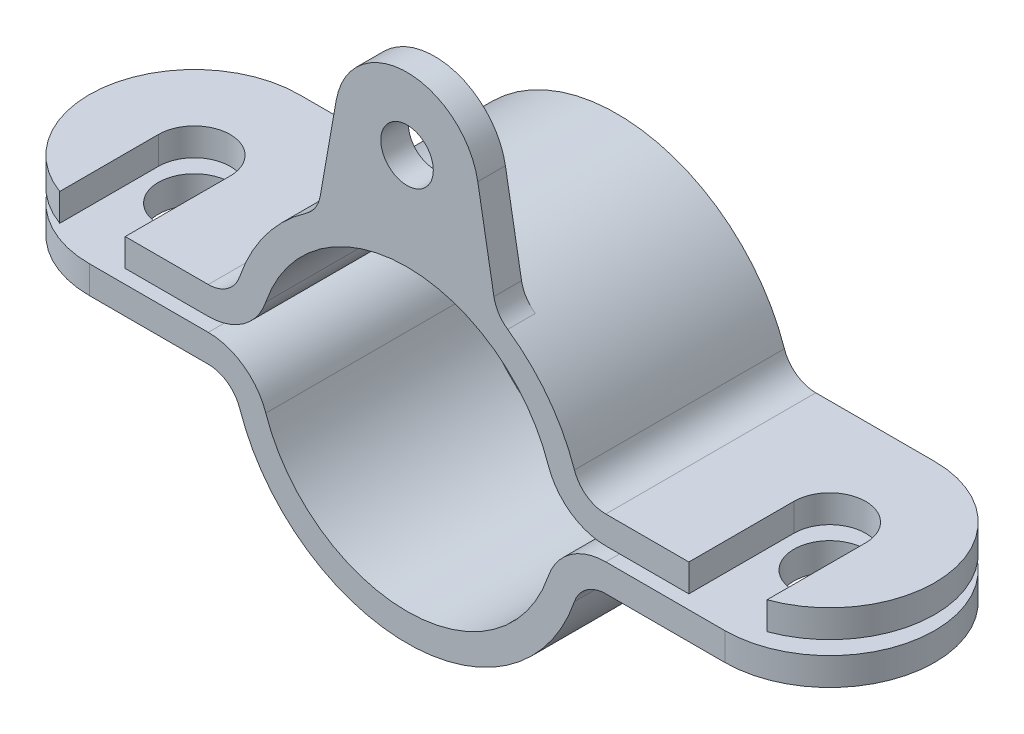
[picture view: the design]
ISO-10303-21;
HEADER;
FILE_DESCRIPTION(('STEP AP214'),'2;1');
FILE_NAME('part.step','',(''),(''),'','','');
FILE_SCHEMA(('AUTOMOTIVE_DESIGN { 1 0 10303 214 1 1 1 1 }'));
ENDSEC;
DATA;
#1=APPLICATION_CONTEXT('core data for automotive mechanical design processes');
#2=APPLICATION_PROTOCOL_DEFINITION('international standard','automotive_design',2000,#1);
#3=PRODUCT_CONTEXT('',#1,'mechanical');
#4=PRODUCT('Part','Part','',(#3));
#5=PRODUCT_RELATED_PRODUCT_CATEGORY('part','',(#4));
#6=PRODUCT_DEFINITION_FORMATION('','',#4);
#7=PRODUCT_DEFINITION_CONTEXT('part definition',#1,'design');
#8=PRODUCT_DEFINITION('design','',#6,#7);
#9=PRODUCT_DEFINITION_SHAPE('','',#8);
#10=(LENGTH_UNIT() NAMED_UNIT(*) SI_UNIT(.MILLI.,.METRE.));
#11=(NAMED_UNIT(*) PLANE_ANGLE_UNIT() SI_UNIT($,.RADIAN.));
#12=(NAMED_UNIT(*) SI_UNIT($,.STERADIAN.) SOLID_ANGLE_UNIT());
#13=UNCERTAINTY_MEASURE_WITH_UNIT(LENGTH_MEASURE(1.E-05),#10,'distance_accuracy_value','');
#14=(GEOMETRIC_REPRESENTATION_CONTEXT(3) GLOBAL_UNCERTAINTY_ASSIGNED_CONTEXT((#13)) GLOBAL_UNIT_ASSIGNED_CONTEXT((#10,
#11,#12)) REPRESENTATION_CONTEXT('',''));
#15=CARTESIAN_POINT('',(0.,0.,0.));
#16=DIRECTION('',(0.,0.,1.));
#17=DIRECTION('',(1.,0.,0.));
#18=AXIS2_PLACEMENT_3D('',#15,#16,#17);
#19=CARTESIAN_POINT('',(57.5,-6.25,-19.));
#20=DIRECTION('',(0.,1.,0.));
#21=DIRECTION('',(-1.,0.,0.));
#22=AXIS2_PLACEMENT_3D('',#19,#20,#21);
#23=CYLINDRICAL_SURFACE('',#22,19.);
#24=DIRECTION('',(0.,1.,0.));
#25=VECTOR('',#24,1.);
#26=CARTESIAN_POINT('',(64.,-6.25,-1.14642892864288));
#27=LINE('',#26,#25);
#28=CARTESIAN_POINT('',(64.,1.25,-1.14642892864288));
#29=VERTEX_POINT('',#28);
#30=CARTESIAN_POINT('',(64.,6.25,-1.14642892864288));
#31=VERTEX_POINT('',#30);
#32=EDGE_CURVE('E236',#29,#31,#27,.T.);
#33=ORIENTED_EDGE('',*,*,#32,.F.);
#34=CARTESIAN_POINT('',(57.5,1.25,-19.));
#35=DIRECTION('',(0.,1.,0.));
#36=DIRECTION('',(0.,0.,1.));
#37=AXIS2_PLACEMENT_3D('',#34,#35,#36);
#38=CIRCLE('',#37,19.);
#39=CARTESIAN_POINT('',(57.5,1.25,-38.));
#40=VERTEX_POINT('',#39);
#41=EDGE_CURVE('E256',#40,#29,#38,.F.);
#42=ORIENTED_EDGE('',*,*,#41,.F.);
#43=DIRECTION('',(0.,-1.,0.));
#44=VECTOR('',#43,1.);
#45=CARTESIAN_POINT('',(57.5,-6.25,-38.));
#46=LINE('',#45,#44);
#47=CARTESIAN_POINT('',(57.5,6.25,-38.));
#48=VERTEX_POINT('',#47);
#49=EDGE_CURVE('E259',#48,#40,#46,.T.);
#50=ORIENTED_EDGE('',*,*,#49,.F.);
#51=CARTESIAN_POINT('',(57.5,6.25,-19.));
#52=DIRECTION('',(0.,1.,0.));
#53=DIRECTION('',(0.,0.,1.));
#54=AXIS2_PLACEMENT_3D('',#51,#52,#53);
#55=CIRCLE('',#54,19.);
#56=EDGE_CURVE('E287',#31,#48,#55,.T.);
#57=ORIENTED_EDGE('',*,*,#56,.F.);
#58=EDGE_LOOP('',(#33,#42,#50,#57));
#59=FACE_BOUND('',#58,.T.);
#60=ADVANCED_FACE('F46',(#59),#23,.T.);
#61=CARTESIAN_POINT('',(0.,0.,-38.));
#62=DIRECTION('',(0.,0.,1.));
#63=DIRECTION('',(1.,0.,0.));
#64=AXIS2_PLACEMENT_3D('',#61,#62,#63);
#65=PLANE('',#64);
#66=CARTESIAN_POINT('',(-35.9713427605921,12.25,-38.));
#67=DIRECTION('',(0.,0.,-1.));
#68=DIRECTION('',(1.,0.,0.));
#69=AXIS2_PLACEMENT_3D('',#66,#67,#68);
#70=CIRCLE('',#69,11.);
#71=CARTESIAN_POINT('',(-25.5585856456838,8.70394736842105,-38.));
#72=VERTEX_POINT('',#71);
#73=CARTESIAN_POINT('',(-35.9713427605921,1.25,-38.));
#74=VERTEX_POINT('',#73);
#75=EDGE_CURVE('E252',#72,#74,#70,.T.);
#76=ORIENTED_EDGE('',*,*,#75,.T.);
#77=DIRECTION('',(-1.,0.,0.));
#78=VECTOR('',#77,1.);
#79=CARTESIAN_POINT('',(-35.9713427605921,1.25,-38.));
#80=LINE('',#79,#78);
#81=CARTESIAN_POINT('',(-57.5,1.25,-38.));
#82=VERTEX_POINT('',#81);
#83=EDGE_CURVE('E372',#74,#82,#80,.T.);
#84=ORIENTED_EDGE('',*,*,#83,.T.);
#85=DIRECTION('',(0.,1.,0.));
#86=VECTOR('',#85,1.);
#87=CARTESIAN_POINT('',(-57.5,6.25,-38.));
#88=LINE('',#87,#86);
#89=CARTESIAN_POINT('',(-57.5,6.25,-38.));
#90=VERTEX_POINT('',#89);
#91=EDGE_CURVE('E266',#82,#90,#88,.T.);
#92=ORIENTED_EDGE('',*,*,#91,.T.);
#93=DIRECTION('',(-1.,0.,0.));
#94=VECTOR('',#93,1.);
#95=CARTESIAN_POINT('',(-31.3837139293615,6.25,-38.));
#96=LINE('',#95,#94);
#97=CARTESIAN_POINT('',(-35.9713427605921,6.25,-38.));
#98=VERTEX_POINT('',#97);
#99=EDGE_CURVE('E291',#98,#90,#96,.T.);
#100=ORIENTED_EDGE('',*,*,#99,.F.);
#101=CARTESIAN_POINT('',(-35.9713427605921,12.25,-38.));
#102=DIRECTION('',(0.,0.,1.));
#103=DIRECTION('',(1.,0.,0.));
#104=AXIS2_PLACEMENT_3D('',#101,#102,#103);
#105=CIRCLE('',#104,6.);
#106=CARTESIAN_POINT('',(-30.2916570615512,10.3157894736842,-38.));
#107=VERTEX_POINT('',#106);
#108=EDGE_CURVE('E260',#98,#107,#105,.T.);
#109=ORIENTED_EDGE('',*,*,#108,.T.);
#110=CARTESIAN_POINT('',(0.,0.,-38.));
#111=DIRECTION('',(0.,0.,1.));
#112=DIRECTION('',(1.,0.,0.));
#113=AXIS2_PLACEMENT_3D('',#110,#111,#112);
#114=CIRCLE('',#113,32.);
#115=CARTESIAN_POINT('',(30.2916570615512,10.3157894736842,-38.));
#116=VERTEX_POINT('',#115);
#117=EDGE_CURVE('E307',#116,#107,#114,.T.);
#118=ORIENTED_EDGE('',*,*,#117,.F.);
#119=CARTESIAN_POINT('',(35.9713427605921,12.25,-38.));
#120=DIRECTION('',(0.,0.,1.));
#121=DIRECTION('',(1.,0.,0.));
#122=AXIS2_PLACEMENT_3D('',#119,#120,#121);
#123=CIRCLE('',#122,6.);
#124=CARTESIAN_POINT('',(35.9713427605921,6.25,-38.));
#125=VERTEX_POINT('',#124);
#126=EDGE_CURVE('E257',#116,#125,#123,.T.);
#127=ORIENTED_EDGE('',*,*,#126,.T.);
#128=DIRECTION('',(-1.,0.,0.));
#129=VECTOR('',#128,1.);
#130=CARTESIAN_POINT('',(31.3837139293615,6.25,-38.));
#131=LINE('',#130,#129);
#132=EDGE_CURVE('E288',#48,#125,#131,.T.);
#133=ORIENTED_EDGE('',*,*,#132,.F.);
#134=ORIENTED_EDGE('',*,*,#49,.T.);
#135=DIRECTION('',(-1.,0.,0.));
#136=VECTOR('',#135,1.);
#137=CARTESIAN_POINT('',(76.5,1.25,-38.));
#138=LINE('',#137,#136);
#139=CARTESIAN_POINT('',(35.9713427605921,1.25,-38.));
#140=VERTEX_POINT('',#139);
#141=EDGE_CURVE('E382',#40,#140,#138,.T.);
#142=ORIENTED_EDGE('',*,*,#141,.T.);
#143=CARTESIAN_POINT('',(35.9713427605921,12.25,-38.));
#144=DIRECTION('',(0.,0.,-1.));
#145=DIRECTION('',(1.,0.,0.));
#146=AXIS2_PLACEMENT_3D('',#143,#144,#145);
#147=CIRCLE('',#146,11.);
#148=CARTESIAN_POINT('',(25.5585856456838,8.70394736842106,-38.));
#149=VERTEX_POINT('',#148);
#150=EDGE_CURVE('E379',#140,#149,#147,.T.);
#151=ORIENTED_EDGE('',*,*,#150,.T.);
#152=CARTESIAN_POINT('',(0.,0.,-38.));
#153=DIRECTION('',(0.,0.,1.));
#154=DIRECTION('',(1.,0.,0.));
#155=AXIS2_PLACEMENT_3D('',#152,#153,#154);
#156=CIRCLE('',#155,27.);
#157=EDGE_CURVE('E317',#149,#72,#156,.T.);
#158=ORIENTED_EDGE('',*,*,#157,.T.);
#159=EDGE_LOOP('',(#76,#84,#92,#100,#109,#118,#127,#133,#134,#142,#151,#158));
#160=FACE_BOUND('',#159,.T.);
#161=ADVANCED_FACE('F420',(#160),#65,.F.);
#162=CARTESIAN_POINT('',(0.,0.,0.));
#163=DIRECTION('',(0.,0.,1.));
#164=DIRECTION('',(1.,0.,0.));
#165=AXIS2_PLACEMENT_3D('',#162,#163,#164);
#166=PLANE('',#165);
#167=DIRECTION('',(0.,1.,0.));
#168=VECTOR('',#167,1.);
#169=CARTESIAN_POINT('',(-51.,-32.,0.));
#170=LINE('',#169,#168);
#171=CARTESIAN_POINT('',(-51.,1.25,0.));
#172=VERTEX_POINT('',#171);
#173=CARTESIAN_POINT('',(-51.,6.25,0.));
#174=VERTEX_POINT('',#173);
#175=EDGE_CURVE('E214',#172,#174,#170,.T.);
#176=ORIENTED_EDGE('',*,*,#175,.F.);
#177=DIRECTION('',(-1.,0.,0.));
#178=VECTOR('',#177,1.);
#179=CARTESIAN_POINT('',(-35.9713427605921,1.25,0.));
#180=LINE('',#179,#178);
#181=CARTESIAN_POINT('',(-35.9713427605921,1.25,0.));
#182=VERTEX_POINT('',#181);
#183=EDGE_CURVE('E363',#182,#172,#180,.T.);
#184=ORIENTED_EDGE('',*,*,#183,.F.);
#185=CARTESIAN_POINT('',(-35.9713427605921,12.25,0.));
#186=DIRECTION('',(0.,0.,-1.));
#187=DIRECTION('',(1.,0.,0.));
#188=AXIS2_PLACEMENT_3D('',#185,#186,#187);
#189=CIRCLE('',#188,11.);
#190=CARTESIAN_POINT('',(-25.5585856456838,8.70394736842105,0.));
#191=VERTEX_POINT('',#190);
#192=EDGE_CURVE('E361',#191,#182,#189,.T.);
#193=ORIENTED_EDGE('',*,*,#192,.F.);
#194=CARTESIAN_POINT('',(0.,0.,0.));
#195=DIRECTION('',(0.,0.,1.));
#196=DIRECTION('',(1.,0.,0.));
#197=AXIS2_PLACEMENT_3D('',#194,#195,#196);
#198=CIRCLE('',#197,27.);
#199=CARTESIAN_POINT('',(25.5585856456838,8.70394736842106,0.));
#200=VERTEX_POINT('',#199);
#201=EDGE_CURVE('E358',#200,#191,#198,.T.);
#202=ORIENTED_EDGE('',*,*,#201,.F.);
#203=CARTESIAN_POINT('',(35.9713427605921,12.25,0.));
#204=DIRECTION('',(0.,0.,-1.));
#205=DIRECTION('',(1.,0.,0.));
#206=AXIS2_PLACEMENT_3D('',#203,#204,#205);
#207=CIRCLE('',#206,11.);
#208=CARTESIAN_POINT('',(35.9713427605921,1.25,0.));
#209=VERTEX_POINT('',#208);
#210=EDGE_CURVE('E355',#209,#200,#207,.T.);
#211=ORIENTED_EDGE('',*,*,#210,.F.);
#212=DIRECTION('',(-1.,0.,0.));
#213=VECTOR('',#212,1.);
#214=CARTESIAN_POINT('',(0.,1.25,0.));
#215=LINE('',#214,#213);
#216=CARTESIAN_POINT('',(51.,1.25,0.));
#217=VERTEX_POINT('',#216);
#218=EDGE_CURVE('E253',#217,#209,#215,.T.);
#219=ORIENTED_EDGE('',*,*,#218,.F.);
#220=DIRECTION('',(0.,1.,0.));
#221=VECTOR('',#220,1.);
#222=CARTESIAN_POINT('',(51.,-32.,0.));
#223=LINE('',#222,#221);
#224=CARTESIAN_POINT('',(51.,6.25,0.));
#225=VERTEX_POINT('',#224);
#226=EDGE_CURVE('E70',#217,#225,#223,.T.);
#227=ORIENTED_EDGE('',*,*,#226,.T.);
#228=DIRECTION('',(-1.,0.,0.));
#229=VECTOR('',#228,1.);
#230=CARTESIAN_POINT('',(31.3837139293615,6.25,0.));
#231=LINE('',#230,#229);
#232=CARTESIAN_POINT('',(35.9713427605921,6.25,0.));
#233=VERTEX_POINT('',#232);
#234=EDGE_CURVE('E264',#225,#233,#231,.T.);
#235=ORIENTED_EDGE('',*,*,#234,.T.);
#236=CARTESIAN_POINT('',(35.9713427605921,12.25,0.));
#237=DIRECTION('',(0.,0.,1.));
#238=DIRECTION('',(1.,0.,0.));
#239=AXIS2_PLACEMENT_3D('',#236,#237,#238);
#240=CIRCLE('',#239,6.);
#241=CARTESIAN_POINT('',(30.2916570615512,10.3157894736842,0.));
#242=VERTEX_POINT('',#241);
#243=EDGE_CURVE('E261',#233,#242,#240,.F.);
#244=ORIENTED_EDGE('',*,*,#243,.T.);
#245=CARTESIAN_POINT('',(0.,0.,0.));
#246=DIRECTION('',(0.,0.,1.));
#247=DIRECTION('',(1.,0.,0.));
#248=AXIS2_PLACEMENT_3D('',#245,#246,#247);
#249=CIRCLE('',#248,32.);
#250=CARTESIAN_POINT('',(18.2153329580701,26.3097252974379,0.));
#251=VERTEX_POINT('',#250);
#252=EDGE_CURVE('E263',#242,#251,#249,.T.);
#253=ORIENTED_EDGE('',*,*,#252,.T.);
#254=CARTESIAN_POINT('',(21.6307078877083,31.2427987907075,0.));
#255=DIRECTION('',(0.,0.,1.));
#256=DIRECTION('',(1.,0.,0.));
#257=AXIS2_PLACEMENT_3D('',#254,#255,#256);
#258=CIRCLE('',#257,6.);
#259=CARTESIAN_POINT('',(15.721861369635,30.200909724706,0.));
#260=VERTEX_POINT('',#259);
#261=EDGE_CURVE('E276',#251,#260,#258,.F.);
#262=ORIENTED_EDGE('',*,*,#261,.T.);
#263=DIRECTION('',(-0.173648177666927,0.984807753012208,0.));
#264=VECTOR('',#263,1.);
#265=CARTESIAN_POINT('',(12.8025007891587,46.7574263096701,0.));
#266=LINE('',#265,#264);
#267=CARTESIAN_POINT('',(12.8025007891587,46.7574263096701,0.));
#268=VERTEX_POINT('',#267);
#269=EDGE_CURVE('E278',#260,#268,#266,.T.);
#270=ORIENTED_EDGE('',*,*,#269,.T.);
#271=CARTESIAN_POINT('',(0.,44.5,0.));
#272=DIRECTION('',(0.,0.,1.));
#273=DIRECTION('',(-1.,0.,0.));
#274=AXIS2_PLACEMENT_3D('',#271,#272,#273);
#275=CIRCLE('',#274,13.);
#276=CARTESIAN_POINT('',(-12.8025007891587,46.7574263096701,0.));
#277=VERTEX_POINT('',#276);
#278=EDGE_CURVE('E333',#268,#277,#275,.T.);
#279=ORIENTED_EDGE('',*,*,#278,.T.);
#280=DIRECTION('',(-0.173648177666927,-0.984807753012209,0.));
#281=VECTOR('',#280,1.);
#282=CARTESIAN_POINT('',(-16.1789319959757,27.6087333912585,0.));
#283=LINE('',#282,#281);
#284=CARTESIAN_POINT('',(-15.721861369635,30.200909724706,0.));
#285=VERTEX_POINT('',#284);
#286=EDGE_CURVE('E283',#277,#285,#283,.T.);
#287=ORIENTED_EDGE('',*,*,#286,.T.);
#288=CARTESIAN_POINT('',(-21.6307078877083,31.2427987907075,0.));
#289=DIRECTION('',(0.,0.,1.));
#290=DIRECTION('',(1.,0.,0.));
#291=AXIS2_PLACEMENT_3D('',#288,#289,#290);
#292=CIRCLE('',#291,6.);
#293=CARTESIAN_POINT('',(-18.2153329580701,26.3097252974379,0.));
#294=VERTEX_POINT('',#293);
#295=EDGE_CURVE('E281',#285,#294,#292,.F.);
#296=ORIENTED_EDGE('',*,*,#295,.T.);
#297=CARTESIAN_POINT('',(-30.2916570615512,10.3157894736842,0.));
#298=VERTEX_POINT('',#297);
#299=EDGE_CURVE('E270',#294,#298,#249,.T.);
#300=ORIENTED_EDGE('',*,*,#299,.T.);
#301=CARTESIAN_POINT('',(-35.9713427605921,12.25,0.));
#302=DIRECTION('',(0.,0.,1.));
#303=DIRECTION('',(1.,0.,0.));
#304=AXIS2_PLACEMENT_3D('',#301,#302,#303);
#305=CIRCLE('',#304,6.);
#306=CARTESIAN_POINT('',(-35.9713427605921,6.25,0.));
#307=VERTEX_POINT('',#306);
#308=EDGE_CURVE('E267',#298,#307,#305,.F.);
#309=ORIENTED_EDGE('',*,*,#308,.T.);
#310=DIRECTION('',(-1.,0.,0.));
#311=VECTOR('',#310,1.);
#312=CARTESIAN_POINT('',(-31.3837139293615,6.25,0.));
#313=LINE('',#312,#311);
#314=EDGE_CURVE('E269',#307,#174,#313,.T.);
#315=ORIENTED_EDGE('',*,*,#314,.T.);
#316=EDGE_LOOP('',(#176,#184,#193,#202,#211,#219,#227,#235,#244,#253,#262,#270,#279,#287,#296,
#300,#309,#315));
#317=FACE_BOUND('',#316,.T.);
#318=CARTESIAN_POINT('',(0.,44.5,0.));
#319=DIRECTION('',(0.,0.,1.));
#320=DIRECTION('',(1.,0.,0.));
#321=AXIS2_PLACEMENT_3D('',#318,#319,#320);
#322=CIRCLE('',#321,4.75);
#323=CARTESIAN_POINT('',(4.75,44.5,0.));
#324=VERTEX_POINT('',#323);
#325=EDGE_CURVE('E274',#324,#324,#322,.T.);
#326=ORIENTED_EDGE('',*,*,#325,.F.);
#327=EDGE_LOOP('',(#326));
#328=FACE_BOUND('',#327,.T.);
#329=ADVANCED_FACE('F404',(#317,#328),#166,.T.);
#330=CARTESIAN_POINT('',(-57.5,6.25,-19.));
#331=DIRECTION('',(0.,-1.,0.));
#332=DIRECTION('',(1.,0.,0.));
#333=AXIS2_PLACEMENT_3D('',#330,#331,#332);
#334=CYLINDRICAL_SURFACE('',#333,19.);
#335=DIRECTION('',(0.,-1.,0.));
#336=VECTOR('',#335,1.);
#337=CARTESIAN_POINT('',(-64.,6.25,-1.14642892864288));
#338=LINE('',#337,#336);
#339=CARTESIAN_POINT('',(-64.,6.25,-1.14642892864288));
#340=VERTEX_POINT('',#339);
#341=CARTESIAN_POINT('',(-64.,1.25,-1.14642892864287));
#342=VERTEX_POINT('',#341);
#343=EDGE_CURVE('E62',#340,#342,#338,.T.);
#344=ORIENTED_EDGE('',*,*,#343,.F.);
#345=CARTESIAN_POINT('',(-57.5,6.25,-19.));
#346=DIRECTION('',(0.,1.,0.));
#347=DIRECTION('',(0.,0.,1.));
#348=AXIS2_PLACEMENT_3D('',#345,#346,#347);
#349=CIRCLE('',#348,19.);
#350=EDGE_CURVE('E231',#90,#340,#349,.T.);
#351=ORIENTED_EDGE('',*,*,#350,.F.);
#352=ORIENTED_EDGE('',*,*,#91,.F.);
#353=CARTESIAN_POINT('',(-57.5,1.25,-19.));
#354=DIRECTION('',(0.,1.,0.));
#355=DIRECTION('',(0.,0.,1.));
#356=AXIS2_PLACEMENT_3D('',#353,#354,#355);
#357=CIRCLE('',#356,19.);
#358=EDGE_CURVE('E345',#342,#82,#357,.F.);
#359=ORIENTED_EDGE('',*,*,#358,.F.);
#360=EDGE_LOOP('',(#344,#351,#352,#359));
#361=FACE_BOUND('',#360,.T.);
#362=ADVANCED_FACE('F49',(#361),#334,.T.);
#363=CARTESIAN_POINT('',(0.,0.,-38.));
#364=DIRECTION('',(0.,0.,1.));
#365=DIRECTION('',(1.,0.,0.));
#366=AXIS2_PLACEMENT_3D('',#363,#364,#365);
#367=CYLINDRICAL_SURFACE('',#366,32.);
#368=ORIENTED_EDGE('',*,*,#299,.F.);
#369=DIRECTION('',(0.,0.,1.));
#370=VECTOR('',#369,1.);
#371=CARTESIAN_POINT('',(-18.2153329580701,26.3097252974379,-38.));
#372=LINE('',#371,#370);
#373=CARTESIAN_POINT('',(-18.2153329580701,26.3097252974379,-5.));
#374=VERTEX_POINT('',#373);
#375=EDGE_CURVE('E296',#294,#374,#372,.F.);
#376=ORIENTED_EDGE('',*,*,#375,.T.);
#377=CARTESIAN_POINT('',(0.,0.,-5.));
#378=DIRECTION('',(0.,0.,-1.));
#379=DIRECTION('',(1.,0.,0.));
#380=AXIS2_PLACEMENT_3D('',#377,#378,#379);
#381=CIRCLE('',#380,32.);
#382=CARTESIAN_POINT('',(18.2153329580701,26.3097252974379,-5.));
#383=VERTEX_POINT('',#382);
#384=EDGE_CURVE('E299',#374,#383,#381,.T.);
#385=ORIENTED_EDGE('',*,*,#384,.T.);
#386=DIRECTION('',(0.,0.,1.));
#387=VECTOR('',#386,1.);
#388=CARTESIAN_POINT('',(18.2153329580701,26.3097252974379,-38.));
#389=LINE('',#388,#387);
#390=EDGE_CURVE('E300',#383,#251,#389,.T.);
#391=ORIENTED_EDGE('',*,*,#390,.T.);
#392=ORIENTED_EDGE('',*,*,#252,.F.);
#393=DIRECTION('',(0.,0.,1.));
#394=VECTOR('',#393,1.);
#395=CARTESIAN_POINT('',(30.2916570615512,10.3157894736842,-38.));
#396=LINE('',#395,#394);
#397=EDGE_CURVE('E303',#242,#116,#396,.F.);
#398=ORIENTED_EDGE('',*,*,#397,.T.);
#399=ORIENTED_EDGE('',*,*,#117,.T.);
#400=DIRECTION('',(0.,0.,1.));
#401=VECTOR('',#400,1.);
#402=CARTESIAN_POINT('',(-30.2916570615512,10.3157894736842,-38.));
#403=LINE('',#402,#401);
#404=EDGE_CURVE('E304',#107,#298,#403,.T.);
#405=ORIENTED_EDGE('',*,*,#404,.T.);
#406=EDGE_LOOP('',(#368,#376,#385,#391,#392,#398,#399,#405));
#407=FACE_BOUND('',#406,.T.);
#408=ADVANCED_FACE('F413',(#407),#367,.T.);
#409=CARTESIAN_POINT('',(31.3837139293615,6.25,-38.));
#410=DIRECTION('',(0.,1.,0.));
#411=DIRECTION('',(0.,0.,1.));
#412=AXIS2_PLACEMENT_3D('',#409,#410,#411);
#413=PLANE('',#412);
#414=DIRECTION('',(0.,0.,-1.));
#415=VECTOR('',#414,1.);
#416=CARTESIAN_POINT('',(64.,6.25,-19.));
#417=LINE('',#416,#415);
#418=CARTESIAN_POINT('',(64.,6.25,-19.));
#419=VERTEX_POINT('',#418);
#420=EDGE_CURVE('E243',#31,#419,#417,.T.);
#421=ORIENTED_EDGE('',*,*,#420,.F.);
#422=ORIENTED_EDGE('',*,*,#56,.T.);
#423=ORIENTED_EDGE('',*,*,#132,.T.);
#424=DIRECTION('',(0.,0.,-1.));
#425=VECTOR('',#424,1.);
#426=CARTESIAN_POINT('',(35.9713427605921,6.25,0.));
#427=LINE('',#426,#425);
#428=EDGE_CURVE('E284',#125,#233,#427,.F.);
#429=ORIENTED_EDGE('',*,*,#428,.T.);
#430=ORIENTED_EDGE('',*,*,#234,.F.);
#431=DIRECTION('',(0.,0.,1.));
#432=VECTOR('',#431,1.);
#433=CARTESIAN_POINT('',(51.,6.25,-19.));
#434=LINE('',#433,#432);
#435=CARTESIAN_POINT('',(51.,6.25,-19.));
#436=VERTEX_POINT('',#435);
#437=EDGE_CURVE('E241',#436,#225,#434,.T.);
#438=ORIENTED_EDGE('',*,*,#437,.F.);
#439=CARTESIAN_POINT('',(57.5,6.25,-19.));
#440=DIRECTION('',(0.,1.,0.));
#441=DIRECTION('',(0.,0.,1.));
#442=AXIS2_PLACEMENT_3D('',#439,#440,#441);
#443=CIRCLE('',#442,6.50000000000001);
#444=EDGE_CURVE('E238',#419,#436,#443,.T.);
#445=ORIENTED_EDGE('',*,*,#444,.F.);
#446=EDGE_LOOP('',(#421,#422,#423,#429,#430,#438,#445));
#447=FACE_BOUND('',#446,.T.);
#448=ADVANCED_FACE('F430',(#447),#413,.T.);
#449=CARTESIAN_POINT('',(-31.3837139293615,6.25,-38.));
#450=DIRECTION('',(0.,1.,0.));
#451=DIRECTION('',(0.,0.,1.));
#452=AXIS2_PLACEMENT_3D('',#449,#450,#451);
#453=PLANE('',#452);
#454=DIRECTION('',(0.,0.,-1.));
#455=VECTOR('',#454,1.);
#456=CARTESIAN_POINT('',(-51.,6.25,-19.));
#457=LINE('',#456,#455);
#458=CARTESIAN_POINT('',(-51.,6.25,-19.));
#459=VERTEX_POINT('',#458);
#460=EDGE_CURVE('E215',#174,#459,#457,.T.);
#461=ORIENTED_EDGE('',*,*,#460,.F.);
#462=ORIENTED_EDGE('',*,*,#314,.F.);
#463=DIRECTION('',(0.,0.,-1.));
#464=VECTOR('',#463,1.);
#465=CARTESIAN_POINT('',(-35.9713427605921,6.25,-38.));
#466=LINE('',#465,#464);
#467=EDGE_CURVE('E289',#307,#98,#466,.T.);
#468=ORIENTED_EDGE('',*,*,#467,.T.);
#469=ORIENTED_EDGE('',*,*,#99,.T.);
#470=ORIENTED_EDGE('',*,*,#350,.T.);
#471=DIRECTION('',(0.,0.,1.));
#472=VECTOR('',#471,1.);
#473=CARTESIAN_POINT('',(-64.,6.25,-19.));
#474=LINE('',#473,#472);
#475=CARTESIAN_POINT('',(-64.,6.25,-19.));
#476=VERTEX_POINT('',#475);
#477=EDGE_CURVE('E210',#476,#340,#474,.T.);
#478=ORIENTED_EDGE('',*,*,#477,.F.);
#479=CARTESIAN_POINT('',(-57.5,6.25,-19.));
#480=DIRECTION('',(0.,1.,0.));
#481=DIRECTION('',(0.,0.,1.));
#482=AXIS2_PLACEMENT_3D('',#479,#480,#481);
#483=CIRCLE('',#482,6.50000000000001);
#484=EDGE_CURVE('E218',#459,#476,#483,.T.);
#485=ORIENTED_EDGE('',*,*,#484,.F.);
#486=EDGE_LOOP('',(#461,#462,#468,#469,#470,#478,#485));
#487=FACE_BOUND('',#486,.T.);
#488=ADVANCED_FACE('F228',(#487),#453,.T.);
#489=CARTESIAN_POINT('',(-16.1789319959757,27.6087333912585,-5.));
#490=DIRECTION('',(-0.984807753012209,0.173648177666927,0.));
#491=DIRECTION('',(-0.173648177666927,-0.984807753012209,0.));
#492=AXIS2_PLACEMENT_3D('',#489,#490,#491);
#493=PLANE('',#492);
#494=DIRECTION('',(-0.173648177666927,-0.984807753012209,0.));
#495=VECTOR('',#494,1.);
#496=CARTESIAN_POINT('',(-16.1789319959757,27.6087333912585,-5.));
#497=LINE('',#496,#495);
#498=CARTESIAN_POINT('',(-12.8025007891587,46.7574263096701,-5.));
#499=VERTEX_POINT('',#498);
#500=CARTESIAN_POINT('',(-15.721861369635,30.200909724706,-5.));
#501=VERTEX_POINT('',#500);
#502=EDGE_CURVE('E313',#499,#501,#497,.T.);
#503=ORIENTED_EDGE('',*,*,#502,.T.);
#504=DIRECTION('',(0.,0.,-1.));
#505=VECTOR('',#504,1.);
#506=CARTESIAN_POINT('',(-15.721861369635,30.200909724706,0.));
#507=LINE('',#506,#505);
#508=EDGE_CURVE('E309',#501,#285,#507,.F.);
#509=ORIENTED_EDGE('',*,*,#508,.T.);
#510=ORIENTED_EDGE('',*,*,#286,.F.);
#511=DIRECTION('',(0.,0.,1.));
#512=VECTOR('',#511,1.);
#513=CARTESIAN_POINT('',(-12.8025007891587,46.7574263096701,-5.));
#514=LINE('',#513,#512);
#515=EDGE_CURVE('E295',#499,#277,#514,.T.);
#516=ORIENTED_EDGE('',*,*,#515,.F.);
#517=EDGE_LOOP('',(#503,#509,#510,#516));
#518=FACE_BOUND('',#517,.T.);
#519=ADVANCED_FACE('F492',(#518),#493,.T.);
#520=CARTESIAN_POINT('',(0.,44.5,-5.));
#521=DIRECTION('',(0.,0.,1.));
#522=DIRECTION('',(1.,0.,0.));
#523=AXIS2_PLACEMENT_3D('',#520,#521,#522);
#524=CYLINDRICAL_SURFACE('',#523,13.);
#525=ORIENTED_EDGE('',*,*,#278,.F.);
#526=DIRECTION('',(0.,0.,1.));
#527=VECTOR('',#526,1.);
#528=CARTESIAN_POINT('',(12.8025007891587,46.7574263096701,-5.));
#529=LINE('',#528,#527);
#530=CARTESIAN_POINT('',(12.8025007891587,46.7574263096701,-5.));
#531=VERTEX_POINT('',#530);
#532=EDGE_CURVE('E327',#531,#268,#529,.T.);
#533=ORIENTED_EDGE('',*,*,#532,.F.);
#534=CARTESIAN_POINT('',(0.,44.5,-5.));
#535=DIRECTION('',(0.,0.,1.));
#536=DIRECTION('',(-1.,0.,0.));
#537=AXIS2_PLACEMENT_3D('',#534,#535,#536);
#538=CIRCLE('',#537,13.);
#539=EDGE_CURVE('E312',#531,#499,#538,.T.);
#540=ORIENTED_EDGE('',*,*,#539,.T.);
#541=ORIENTED_EDGE('',*,*,#515,.T.);
#542=EDGE_LOOP('',(#525,#533,#540,#541));
#543=FACE_BOUND('',#542,.T.);
#544=ADVANCED_FACE('F495',(#543),#524,.T.);
#545=CARTESIAN_POINT('',(12.8025007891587,46.7574263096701,-5.));
#546=DIRECTION('',(0.984807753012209,0.173648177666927,0.));
#547=DIRECTION('',(-0.173648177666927,0.984807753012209,0.));
#548=AXIS2_PLACEMENT_3D('',#545,#546,#547);
#549=PLANE('',#548);
#550=ORIENTED_EDGE('',*,*,#269,.F.);
#551=DIRECTION('',(0.,0.,-1.));
#552=VECTOR('',#551,1.);
#553=CARTESIAN_POINT('',(15.721861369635,30.200909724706,-5.));
#554=LINE('',#553,#552);
#555=CARTESIAN_POINT('',(15.721861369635,30.200909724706,-5.));
#556=VERTEX_POINT('',#555);
#557=EDGE_CURVE('E292',#260,#556,#554,.T.);
#558=ORIENTED_EDGE('',*,*,#557,.T.);
#559=DIRECTION('',(-0.173648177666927,0.984807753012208,0.));
#560=VECTOR('',#559,1.);
#561=CARTESIAN_POINT('',(12.8025007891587,46.7574263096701,-5.));
#562=LINE('',#561,#560);
#563=EDGE_CURVE('E294',#556,#531,#562,.T.);
#564=ORIENTED_EDGE('',*,*,#563,.T.);
#565=ORIENTED_EDGE('',*,*,#532,.T.);
#566=EDGE_LOOP('',(#550,#558,#564,#565));
#567=FACE_BOUND('',#566,.T.);
#568=ADVANCED_FACE('F490',(#567),#549,.T.);
#569=CARTESIAN_POINT('',(0.,0.,-5.));
#570=DIRECTION('',(0.,0.,1.));
#571=DIRECTION('',(1.,0.,0.));
#572=AXIS2_PLACEMENT_3D('',#569,#570,#571);
#573=PLANE('',#572);
#574=CARTESIAN_POINT('',(0.,44.5,-5.));
#575=DIRECTION('',(0.,0.,1.));
#576=DIRECTION('',(1.,0.,0.));
#577=AXIS2_PLACEMENT_3D('',#574,#575,#576);
#578=CIRCLE('',#577,4.75);
#579=CARTESIAN_POINT('',(4.75,44.5,-5.));
#580=VERTEX_POINT('',#579);
#581=EDGE_CURVE('E280',#580,#580,#578,.T.);
#582=ORIENTED_EDGE('',*,*,#581,.T.);
#583=EDGE_LOOP('',(#582));
#584=FACE_BOUND('',#583,.T.);
#585=ORIENTED_EDGE('',*,*,#384,.F.);
#586=CARTESIAN_POINT('',(-21.6307078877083,31.2427987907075,-5.));
#587=DIRECTION('',(0.,0.,1.));
#588=DIRECTION('',(1.,0.,0.));
#589=AXIS2_PLACEMENT_3D('',#586,#587,#588);
#590=CIRCLE('',#589,6.);
#591=EDGE_CURVE('E275',#374,#501,#590,.T.);
#592=ORIENTED_EDGE('',*,*,#591,.T.);
#593=ORIENTED_EDGE('',*,*,#502,.F.);
#594=ORIENTED_EDGE('',*,*,#539,.F.);
#595=ORIENTED_EDGE('',*,*,#563,.F.);
#596=CARTESIAN_POINT('',(21.6307078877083,31.2427987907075,-5.));
#597=DIRECTION('',(0.,0.,1.));
#598=DIRECTION('',(1.,0.,0.));
#599=AXIS2_PLACEMENT_3D('',#596,#597,#598);
#600=CIRCLE('',#599,6.);
#601=EDGE_CURVE('E271',#556,#383,#600,.T.);
#602=ORIENTED_EDGE('',*,*,#601,.T.);
#603=EDGE_LOOP('',(#585,#592,#593,#594,#595,#602));
#604=FACE_BOUND('',#603,.T.);
#605=ADVANCED_FACE('F486',(#584,#604),#573,.F.);
#606=CARTESIAN_POINT('',(0.,44.5,-5.));
#607=DIRECTION('',(0.,0.,1.));
#608=DIRECTION('',(1.,0.,0.));
#609=AXIS2_PLACEMENT_3D('',#606,#607,#608);
#610=CYLINDRICAL_SURFACE('',#609,4.75);
#611=ORIENTED_EDGE('',*,*,#581,.F.);
#612=EDGE_LOOP('',(#611));
#613=FACE_BOUND('',#612,.T.);
#614=ORIENTED_EDGE('',*,*,#325,.T.);
#615=EDGE_LOOP('',(#614));
#616=FACE_BOUND('',#615,.T.);
#617=ADVANCED_FACE('F482',(#613,#616),#610,.F.);
#618=CARTESIAN_POINT('',(-21.6307078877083,31.2427987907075,-38.));
#619=DIRECTION('',(0.,0.,1.));
#620=DIRECTION('',(1.,0.,0.));
#621=AXIS2_PLACEMENT_3D('',#618,#619,#620);
#622=CYLINDRICAL_SURFACE('',#621,6.);
#623=ORIENTED_EDGE('',*,*,#591,.F.);
#624=ORIENTED_EDGE('',*,*,#375,.F.);
#625=ORIENTED_EDGE('',*,*,#295,.F.);
#626=ORIENTED_EDGE('',*,*,#508,.F.);
#627=EDGE_LOOP('',(#623,#624,#625,#626));
#628=FACE_BOUND('',#627,.T.);
#629=ADVANCED_FACE('F485',(#628),#622,.F.);
#630=CARTESIAN_POINT('',(21.6307078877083,31.2427987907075,-38.));
#631=DIRECTION('',(0.,0.,1.));
#632=DIRECTION('',(1.,0.,0.));
#633=AXIS2_PLACEMENT_3D('',#630,#631,#632);
#634=CYLINDRICAL_SURFACE('',#633,6.);
#635=ORIENTED_EDGE('',*,*,#601,.F.);
#636=ORIENTED_EDGE('',*,*,#557,.F.);
#637=ORIENTED_EDGE('',*,*,#261,.F.);
#638=ORIENTED_EDGE('',*,*,#390,.F.);
#639=EDGE_LOOP('',(#635,#636,#637,#638));
#640=FACE_BOUND('',#639,.T.);
#641=ADVANCED_FACE('F509',(#640),#634,.F.);
#642=CARTESIAN_POINT('',(-35.9713427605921,12.25,-38.));
#643=DIRECTION('',(0.,0.,1.));
#644=DIRECTION('',(1.,0.,0.));
#645=AXIS2_PLACEMENT_3D('',#642,#643,#644);
#646=CYLINDRICAL_SURFACE('',#645,6.);
#647=ORIENTED_EDGE('',*,*,#108,.F.);
#648=ORIENTED_EDGE('',*,*,#467,.F.);
#649=ORIENTED_EDGE('',*,*,#308,.F.);
#650=ORIENTED_EDGE('',*,*,#404,.F.);
#651=EDGE_LOOP('',(#647,#648,#649,#650));
#652=FACE_BOUND('',#651,.T.);
#653=ADVANCED_FACE('F411',(#652),#646,.F.);
#654=CARTESIAN_POINT('',(35.9713427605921,12.25,-38.));
#655=DIRECTION('',(0.,0.,1.));
#656=DIRECTION('',(1.,0.,0.));
#657=AXIS2_PLACEMENT_3D('',#654,#655,#656);
#658=CYLINDRICAL_SURFACE('',#657,6.);
#659=ORIENTED_EDGE('',*,*,#126,.F.);
#660=ORIENTED_EDGE('',*,*,#397,.F.);
#661=ORIENTED_EDGE('',*,*,#243,.F.);
#662=ORIENTED_EDGE('',*,*,#428,.F.);
#663=EDGE_LOOP('',(#659,#660,#661,#662));
#664=FACE_BOUND('',#663,.T.);
#665=ADVANCED_FACE('F425',(#664),#658,.F.);
#666=CARTESIAN_POINT('',(-35.9713427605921,1.25,-38.));
#667=DIRECTION('',(0.,1.,0.));
#668=DIRECTION('',(0.,0.,1.));
#669=AXIS2_PLACEMENT_3D('',#666,#667,#668);
#670=PLANE('',#669);
#671=ORIENTED_EDGE('',*,*,#183,.T.);
#672=DIRECTION('',(0.,0.,-1.));
#673=VECTOR('',#672,1.);
#674=CARTESIAN_POINT('',(-51.,1.25,-38.));
#675=LINE('',#674,#673);
#676=CARTESIAN_POINT('',(-51.,1.25,-19.));
#677=VERTEX_POINT('',#676);
#678=EDGE_CURVE('E12',#172,#677,#675,.T.);
#679=ORIENTED_EDGE('',*,*,#678,.T.);
#680=CARTESIAN_POINT('',(-57.5,1.25,-19.));
#681=DIRECTION('',(0.,1.,0.));
#682=DIRECTION('',(0.,0.,1.));
#683=AXIS2_PLACEMENT_3D('',#680,#681,#682);
#684=CIRCLE('',#683,6.50000000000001);
#685=CARTESIAN_POINT('',(-64.,1.25,-19.));
#686=VERTEX_POINT('',#685);
#687=EDGE_CURVE('E55',#677,#686,#684,.T.);
#688=ORIENTED_EDGE('',*,*,#687,.T.);
#689=DIRECTION('',(0.,0.,1.));
#690=VECTOR('',#689,1.);
#691=CARTESIAN_POINT('',(-64.,1.25,-38.));
#692=LINE('',#691,#690);
#693=EDGE_CURVE('E211',#686,#342,#692,.T.);
#694=ORIENTED_EDGE('',*,*,#693,.T.);
#695=ORIENTED_EDGE('',*,*,#358,.T.);
#696=ORIENTED_EDGE('',*,*,#83,.F.);
#697=DIRECTION('',(0.,0.,1.));
#698=VECTOR('',#697,1.);
#699=CARTESIAN_POINT('',(-35.9713427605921,1.25,-38.));
#700=LINE('',#699,#698);
#701=EDGE_CURVE('E349',#74,#182,#700,.T.);
#702=ORIENTED_EDGE('',*,*,#701,.T.);
#703=EDGE_LOOP('',(#671,#679,#688,#694,#695,#696,#702));
#704=FACE_BOUND('',#703,.T.);
#705=ADVANCED_FACE('F396',(#704),#670,.F.);
#706=CARTESIAN_POINT('',(-35.9713427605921,12.25,-38.));
#707=DIRECTION('',(0.,0.,1.));
#708=DIRECTION('',(1.,0.,0.));
#709=AXIS2_PLACEMENT_3D('',#706,#707,#708);
#710=CYLINDRICAL_SURFACE('',#709,11.);
#711=ORIENTED_EDGE('',*,*,#192,.T.);
#712=ORIENTED_EDGE('',*,*,#701,.F.);
#713=ORIENTED_EDGE('',*,*,#75,.F.);
#714=DIRECTION('',(0.,0.,1.));
#715=VECTOR('',#714,1.);
#716=CARTESIAN_POINT('',(-25.5585856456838,8.70394736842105,-38.));
#717=LINE('',#716,#715);
#718=EDGE_CURVE('E359',#72,#191,#717,.T.);
#719=ORIENTED_EDGE('',*,*,#718,.T.);
#720=EDGE_LOOP('',(#711,#712,#713,#719));
#721=FACE_BOUND('',#720,.T.);
#722=ADVANCED_FACE('F451',(#721),#710,.T.);
#723=CARTESIAN_POINT('',(0.,0.,-38.));
#724=DIRECTION('',(0.,0.,1.));
#725=DIRECTION('',(1.,0.,0.));
#726=AXIS2_PLACEMENT_3D('',#723,#724,#725);
#727=CYLINDRICAL_SURFACE('',#726,27.);
#728=ORIENTED_EDGE('',*,*,#201,.T.);
#729=ORIENTED_EDGE('',*,*,#718,.F.);
#730=ORIENTED_EDGE('',*,*,#157,.F.);
#731=DIRECTION('',(0.,0.,1.));
#732=VECTOR('',#731,1.);
#733=CARTESIAN_POINT('',(25.5585856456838,8.70394736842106,-38.));
#734=LINE('',#733,#732);
#735=EDGE_CURVE('E356',#149,#200,#734,.T.);
#736=ORIENTED_EDGE('',*,*,#735,.T.);
#737=EDGE_LOOP('',(#728,#729,#730,#736));
#738=FACE_BOUND('',#737,.T.);
#739=ADVANCED_FACE('F447',(#738),#727,.F.);
#740=CARTESIAN_POINT('',(35.9713427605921,12.25,-38.));
#741=DIRECTION('',(0.,0.,1.));
#742=DIRECTION('',(1.,0.,0.));
#743=AXIS2_PLACEMENT_3D('',#740,#741,#742);
#744=CYLINDRICAL_SURFACE('',#743,11.);
#745=ORIENTED_EDGE('',*,*,#210,.T.);
#746=ORIENTED_EDGE('',*,*,#735,.F.);
#747=ORIENTED_EDGE('',*,*,#150,.F.);
#748=DIRECTION('',(0.,0.,1.));
#749=VECTOR('',#748,1.);
#750=CARTESIAN_POINT('',(35.9713427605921,1.25,-38.));
#751=LINE('',#750,#749);
#752=EDGE_CURVE('E352',#140,#209,#751,.T.);
#753=ORIENTED_EDGE('',*,*,#752,.T.);
#754=EDGE_LOOP('',(#745,#746,#747,#753));
#755=FACE_BOUND('',#754,.T.);
#756=ADVANCED_FACE('F443',(#755),#744,.T.);
#757=CARTESIAN_POINT('',(76.5,1.25,-38.));
#758=DIRECTION('',(0.,1.,0.));
#759=DIRECTION('',(0.,0.,1.));
#760=AXIS2_PLACEMENT_3D('',#757,#758,#759);
#761=PLANE('',#760);
#762=ORIENTED_EDGE('',*,*,#41,.T.);
#763=DIRECTION('',(0.,0.,-1.));
#764=VECTOR('',#763,1.);
#765=CARTESIAN_POINT('',(64.,1.25,-38.));
#766=LINE('',#765,#764);
#767=CARTESIAN_POINT('',(64.,1.25,-19.));
#768=VERTEX_POINT('',#767);
#769=EDGE_CURVE('E392',#29,#768,#766,.T.);
#770=ORIENTED_EDGE('',*,*,#769,.T.);
#771=CARTESIAN_POINT('',(57.5,1.25,-19.));
#772=DIRECTION('',(0.,1.,0.));
#773=DIRECTION('',(0.,0.,1.));
#774=AXIS2_PLACEMENT_3D('',#771,#772,#773);
#775=CIRCLE('',#774,6.50000000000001);
#776=CARTESIAN_POINT('',(51.,1.25,-19.));
#777=VERTEX_POINT('',#776);
#778=EDGE_CURVE('E389',#768,#777,#775,.T.);
#779=ORIENTED_EDGE('',*,*,#778,.T.);
#780=DIRECTION('',(0.,0.,1.));
#781=VECTOR('',#780,1.);
#782=CARTESIAN_POINT('',(51.,1.25,-38.));
#783=LINE('',#782,#781);
#784=EDGE_CURVE('E255',#777,#217,#783,.T.);
#785=ORIENTED_EDGE('',*,*,#784,.T.);
#786=ORIENTED_EDGE('',*,*,#218,.T.);
#787=ORIENTED_EDGE('',*,*,#752,.F.);
#788=ORIENTED_EDGE('',*,*,#141,.F.);
#789=EDGE_LOOP('',(#762,#770,#779,#785,#786,#787,#788));
#790=FACE_BOUND('',#789,.T.);
#791=ADVANCED_FACE('F438',(#790),#761,.F.);
#792=CARTESIAN_POINT('',(57.5,-32.,-19.));
#793=DIRECTION('',(0.,1.,0.));
#794=DIRECTION('',(0.,0.,1.));
#795=AXIS2_PLACEMENT_3D('',#792,#793,#794);
#796=CYLINDRICAL_SURFACE('',#795,6.50000000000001);
#797=DIRECTION('',(0.,1.,0.));
#798=VECTOR('',#797,1.);
#799=CARTESIAN_POINT('',(64.,-32.,-19.));
#800=LINE('',#799,#798);
#801=EDGE_CURVE('E225',#768,#419,#800,.T.);
#802=ORIENTED_EDGE('',*,*,#801,.T.);
#803=ORIENTED_EDGE('',*,*,#444,.T.);
#804=DIRECTION('',(0.,1.,0.));
#805=VECTOR('',#804,1.);
#806=CARTESIAN_POINT('',(51.,-32.,-19.));
#807=LINE('',#806,#805);
#808=EDGE_CURVE('E246',#777,#436,#807,.T.);
#809=ORIENTED_EDGE('',*,*,#808,.F.);
#810=ORIENTED_EDGE('',*,*,#778,.F.);
#811=EDGE_LOOP('',(#802,#803,#809,#810));
#812=FACE_BOUND('',#811,.T.);
#813=ADVANCED_FACE('F481',(#812),#796,.F.);
#814=CARTESIAN_POINT('',(51.,-32.,-19.));
#815=DIRECTION('',(-1.,0.,0.));
#816=DIRECTION('',(0.,0.,1.));
#817=AXIS2_PLACEMENT_3D('',#814,#815,#816);
#818=PLANE('',#817);
#819=ORIENTED_EDGE('',*,*,#808,.T.);
#820=ORIENTED_EDGE('',*,*,#437,.T.);
#821=ORIENTED_EDGE('',*,*,#226,.F.);
#822=ORIENTED_EDGE('',*,*,#784,.F.);
#823=EDGE_LOOP('',(#819,#820,#821,#822));
#824=FACE_BOUND('',#823,.T.);
#825=ADVANCED_FACE('F520',(#824),#818,.F.);
#826=CARTESIAN_POINT('',(64.,-32.,-19.));
#827=DIRECTION('',(1.,0.,0.));
#828=DIRECTION('',(0.,0.,-1.));
#829=AXIS2_PLACEMENT_3D('',#826,#827,#828);
#830=PLANE('',#829);
#831=ORIENTED_EDGE('',*,*,#32,.T.);
#832=ORIENTED_EDGE('',*,*,#420,.T.);
#833=ORIENTED_EDGE('',*,*,#801,.F.);
#834=ORIENTED_EDGE('',*,*,#769,.F.);
#835=EDGE_LOOP('',(#831,#832,#833,#834));
#836=FACE_BOUND('',#835,.T.);
#837=ADVANCED_FACE('F524',(#836),#830,.F.);
#838=CARTESIAN_POINT('',(-57.5,-32.,-19.));
#839=DIRECTION('',(0.,1.,0.));
#840=DIRECTION('',(0.,0.,1.));
#841=AXIS2_PLACEMENT_3D('',#838,#839,#840);
#842=CYLINDRICAL_SURFACE('',#841,6.50000000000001);
#843=DIRECTION('',(0.,1.,0.));
#844=VECTOR('',#843,1.);
#845=CARTESIAN_POINT('',(-51.,-32.,-19.));
#846=LINE('',#845,#844);
#847=EDGE_CURVE('E221',#677,#459,#846,.T.);
#848=ORIENTED_EDGE('',*,*,#847,.T.);
#849=ORIENTED_EDGE('',*,*,#484,.T.);
#850=DIRECTION('',(0.,1.,0.));
#851=VECTOR('',#850,1.);
#852=CARTESIAN_POINT('',(-64.,-32.,-19.));
#853=LINE('',#852,#851);
#854=EDGE_CURVE('E206',#686,#476,#853,.T.);
#855=ORIENTED_EDGE('',*,*,#854,.F.);
#856=ORIENTED_EDGE('',*,*,#687,.F.);
#857=EDGE_LOOP('',(#848,#849,#855,#856));
#858=FACE_BOUND('',#857,.T.);
#859=ADVANCED_FACE('F219',(#858),#842,.F.);
#860=CARTESIAN_POINT('',(-51.,-32.,-19.));
#861=DIRECTION('',(1.,0.,0.));
#862=DIRECTION('',(0.,0.,-1.));
#863=AXIS2_PLACEMENT_3D('',#860,#861,#862);
#864=PLANE('',#863);
#865=ORIENTED_EDGE('',*,*,#175,.T.);
#866=ORIENTED_EDGE('',*,*,#460,.T.);
#867=ORIENTED_EDGE('',*,*,#847,.F.);
#868=ORIENTED_EDGE('',*,*,#678,.F.);
#869=EDGE_LOOP('',(#865,#866,#867,#868));
#870=FACE_BOUND('',#869,.T.);
#871=ADVANCED_FACE('F399',(#870),#864,.F.);
#872=CARTESIAN_POINT('',(-64.,-32.,-19.));
#873=DIRECTION('',(-1.,0.,0.));
#874=DIRECTION('',(0.,0.,1.));
#875=AXIS2_PLACEMENT_3D('',#872,#873,#874);
#876=PLANE('',#875);
#877=ORIENTED_EDGE('',*,*,#343,.T.);
#878=ORIENTED_EDGE('',*,*,#693,.F.);
#879=ORIENTED_EDGE('',*,*,#854,.T.);
#880=ORIENTED_EDGE('',*,*,#477,.T.);
#881=EDGE_LOOP('',(#877,#878,#879,#880));
#882=FACE_BOUND('',#881,.T.);
#883=ADVANCED_FACE('F208',(#882),#876,.F.);
#884=CLOSED_SHELL('',(#60,#161,#329,#362,#408,#448,#488,#519,#544,#568,#605,#617,#629,#641,#653,
#665,#705,#722,#739,#756,#791,#813,#825,#837,#859,#871,#883));
#885=MANIFOLD_SOLID_BREP('B2',#884);
#886=CARTESIAN_POINT('',(31.3837139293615,-6.25,-38.));
#887=DIRECTION('',(0.,-1.,0.));
#888=DIRECTION('',(0.,0.,-1.));
#889=AXIS2_PLACEMENT_3D('',#886,#887,#888);
#890=PLANE('',#889);
#891=CARTESIAN_POINT('',(57.5,-6.25,-19.));
#892=DIRECTION('',(0.,-1.,0.));
#893=DIRECTION('',(0.,0.,-1.));
#894=AXIS2_PLACEMENT_3D('',#891,#892,#893);
#895=CIRCLE('',#894,6.5);
#896=CARTESIAN_POINT('',(57.5,-6.25,-25.5));
#897=VERTEX_POINT('',#896);
#898=EDGE_CURVE('E834',#897,#897,#895,.T.);
#899=ORIENTED_EDGE('',*,*,#898,.F.);
#900=EDGE_LOOP('',(#899));
#901=FACE_BOUND('',#900,.T.);
#902=DIRECTION('',(1.,0.,0.));
#903=VECTOR('',#902,1.);
#904=CARTESIAN_POINT('',(31.3837139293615,-6.25,0.));
#905=LINE('',#904,#903);
#906=CARTESIAN_POINT('',(35.9713427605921,-6.25,0.));
#907=VERTEX_POINT('',#906);
#908=CARTESIAN_POINT('',(57.5,-6.25,0.));
#909=VERTEX_POINT('',#908);
#910=EDGE_CURVE('E864',#907,#909,#905,.T.);
#911=ORIENTED_EDGE('',*,*,#910,.F.);
#912=DIRECTION('',(0.,0.,-1.));
#913=VECTOR('',#912,1.);
#914=CARTESIAN_POINT('',(35.9713427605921,-6.25,-38.));
#915=LINE('',#914,#913);
#916=CARTESIAN_POINT('',(35.9713427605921,-6.25,-38.));
#917=VERTEX_POINT('',#916);
#918=EDGE_CURVE('E896',#907,#917,#915,.T.);
#919=ORIENTED_EDGE('',*,*,#918,.T.);
#920=DIRECTION('',(1.,0.,0.));
#921=VECTOR('',#920,1.);
#922=CARTESIAN_POINT('',(31.3837139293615,-6.25,-38.));
#923=LINE('',#922,#921);
#924=CARTESIAN_POINT('',(57.5,-6.25,-38.));
#925=VERTEX_POINT('',#924);
#926=EDGE_CURVE('E867',#917,#925,#923,.T.);
#927=ORIENTED_EDGE('',*,*,#926,.T.);
#928=CARTESIAN_POINT('',(57.5,-6.25,-19.));
#929=DIRECTION('',(0.,-1.,0.));
#930=DIRECTION('',(0.,0.,-1.));
#931=AXIS2_PLACEMENT_3D('',#928,#929,#930);
#932=CIRCLE('',#931,19.);
#933=EDGE_CURVE('E880',#925,#909,#932,.T.);
#934=ORIENTED_EDGE('',*,*,#933,.T.);
#935=EDGE_LOOP('',(#911,#919,#927,#934));
#936=FACE_BOUND('',#935,.T.);
#937=ADVANCED_FACE('F718',(#901,#936),#890,.T.);
#938=CARTESIAN_POINT('',(35.9713427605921,-12.25,-38.));
#939=DIRECTION('',(0.,0.,1.));
#940=DIRECTION('',(1.,0.,0.));
#941=AXIS2_PLACEMENT_3D('',#938,#939,#940);
#942=CYLINDRICAL_SURFACE('',#941,6.);
#943=CARTESIAN_POINT('',(35.9713427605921,-12.25,-38.));
#944=DIRECTION('',(0.,0.,1.));
#945=DIRECTION('',(1.,0.,0.));
#946=AXIS2_PLACEMENT_3D('',#943,#944,#945);
#947=CIRCLE('',#946,6.);
#948=CARTESIAN_POINT('',(30.2916570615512,-10.3157894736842,-38.));
#949=VERTEX_POINT('',#948);
#950=EDGE_CURVE('E727',#917,#949,#947,.T.);
#951=ORIENTED_EDGE('',*,*,#950,.F.);
#952=ORIENTED_EDGE('',*,*,#918,.F.);
#953=CARTESIAN_POINT('',(35.9713427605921,-12.25,0.));
#954=DIRECTION('',(0.,0.,1.));
#955=DIRECTION('',(1.,0.,0.));
#956=AXIS2_PLACEMENT_3D('',#953,#954,#955);
#957=CIRCLE('',#956,6.);
#958=CARTESIAN_POINT('',(30.2916570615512,-10.3157894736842,0.));
#959=VERTEX_POINT('',#958);
#960=EDGE_CURVE('E742',#959,#907,#957,.F.);
#961=ORIENTED_EDGE('',*,*,#960,.F.);
#962=DIRECTION('',(0.,0.,1.));
#963=VECTOR('',#962,1.);
#964=CARTESIAN_POINT('',(30.2916570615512,-10.3157894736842,-38.));
#965=LINE('',#964,#963);
#966=EDGE_CURVE('E891',#949,#959,#965,.T.);
#967=ORIENTED_EDGE('',*,*,#966,.F.);
#968=EDGE_LOOP('',(#951,#952,#961,#967));
#969=FACE_BOUND('',#968,.T.);
#970=ADVANCED_FACE('F720',(#969),#942,.F.);
#971=CARTESIAN_POINT('',(0.,0.,-38.));
#972=DIRECTION('',(0.,0.,1.));
#973=DIRECTION('',(1.,0.,0.));
#974=AXIS2_PLACEMENT_3D('',#971,#972,#973);
#975=CYLINDRICAL_SURFACE('',#974,32.);
#976=CARTESIAN_POINT('',(0.,0.,0.));
#977=DIRECTION('',(0.,0.,1.));
#978=DIRECTION('',(1.,0.,0.));
#979=AXIS2_PLACEMENT_3D('',#976,#977,#978);
#980=CIRCLE('',#979,32.);
#981=CARTESIAN_POINT('',(-30.2916570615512,-10.3157894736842,0.));
#982=VERTEX_POINT('',#981);
#983=EDGE_CURVE('E873',#982,#959,#980,.T.);
#984=ORIENTED_EDGE('',*,*,#983,.F.);
#985=DIRECTION('',(0.,0.,1.));
#986=VECTOR('',#985,1.);
#987=CARTESIAN_POINT('',(-30.2916570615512,-10.3157894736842,-38.));
#988=LINE('',#987,#986);
#989=CARTESIAN_POINT('',(-30.2916570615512,-10.3157894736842,-38.));
#990=VERTEX_POINT('',#989);
#991=EDGE_CURVE('E894',#982,#990,#988,.F.);
#992=ORIENTED_EDGE('',*,*,#991,.T.);
#993=CARTESIAN_POINT('',(0.,0.,-38.));
#994=DIRECTION('',(0.,0.,1.));
#995=DIRECTION('',(1.,0.,0.));
#996=AXIS2_PLACEMENT_3D('',#993,#994,#995);
#997=CIRCLE('',#996,32.);
#998=EDGE_CURVE('E863',#990,#949,#997,.T.);
#999=ORIENTED_EDGE('',*,*,#998,.T.);
#1000=ORIENTED_EDGE('',*,*,#966,.T.);
#1001=EDGE_LOOP('',(#984,#992,#999,#1000));
#1002=FACE_BOUND('',#1001,.T.);
#1003=ADVANCED_FACE('F932',(#1002),#975,.T.);
#1004=CARTESIAN_POINT('',(-35.9713427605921,-12.25,-38.));
#1005=DIRECTION('',(0.,0.,1.));
#1006=DIRECTION('',(1.,0.,0.));
#1007=AXIS2_PLACEMENT_3D('',#1004,#1005,#1006);
#1008=CYLINDRICAL_SURFACE('',#1007,6.);
#1009=CARTESIAN_POINT('',(-35.9713427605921,-12.25,-38.));
#1010=DIRECTION('',(0.,0.,1.));
#1011=DIRECTION('',(1.,0.,0.));
#1012=AXIS2_PLACEMENT_3D('',#1009,#1010,#1011);
#1013=CIRCLE('',#1012,6.);
#1014=CARTESIAN_POINT('',(-35.9713427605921,-6.25,-38.));
#1015=VERTEX_POINT('',#1014);
#1016=EDGE_CURVE('E900',#990,#1015,#1013,.T.);
#1017=ORIENTED_EDGE('',*,*,#1016,.F.);
#1018=ORIENTED_EDGE('',*,*,#991,.F.);
#1019=CARTESIAN_POINT('',(-35.9713427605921,-12.25,0.));
#1020=DIRECTION('',(0.,0.,1.));
#1021=DIRECTION('',(1.,0.,0.));
#1022=AXIS2_PLACEMENT_3D('',#1019,#1020,#1021);
#1023=CIRCLE('',#1022,6.);
#1024=CARTESIAN_POINT('',(-35.9713427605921,-6.25,0.));
#1025=VERTEX_POINT('',#1024);
#1026=EDGE_CURVE('E898',#1025,#982,#1023,.F.);
#1027=ORIENTED_EDGE('',*,*,#1026,.F.);
#1028=DIRECTION('',(0.,0.,-1.));
#1029=VECTOR('',#1028,1.);
#1030=CARTESIAN_POINT('',(-35.9713427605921,-6.25,0.));
#1031=LINE('',#1030,#1029);
#1032=EDGE_CURVE('E888',#1015,#1025,#1031,.F.);
#1033=ORIENTED_EDGE('',*,*,#1032,.F.);
#1034=EDGE_LOOP('',(#1017,#1018,#1027,#1033));
#1035=FACE_BOUND('',#1034,.T.);
#1036=ADVANCED_FACE('F935',(#1035),#1008,.F.);
#1037=CARTESIAN_POINT('',(-31.3837139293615,-6.25,-38.));
#1038=DIRECTION('',(0.,-1.,0.));
#1039=DIRECTION('',(0.,0.,-1.));
#1040=AXIS2_PLACEMENT_3D('',#1037,#1038,#1039);
#1041=PLANE('',#1040);
#1042=CARTESIAN_POINT('',(-57.5,-6.25,-19.));
#1043=DIRECTION('',(0.,-1.,0.));
#1044=DIRECTION('',(0.,0.,-1.));
#1045=AXIS2_PLACEMENT_3D('',#1042,#1043,#1044);
#1046=CIRCLE('',#1045,6.5);
#1047=CARTESIAN_POINT('',(-57.5,-6.25,-25.5));
#1048=VERTEX_POINT('',#1047);
#1049=EDGE_CURVE('E905',#1048,#1048,#1046,.T.);
#1050=ORIENTED_EDGE('',*,*,#1049,.F.);
#1051=EDGE_LOOP('',(#1050));
#1052=FACE_BOUND('',#1051,.T.);
#1053=DIRECTION('',(1.,0.,0.));
#1054=VECTOR('',#1053,1.);
#1055=CARTESIAN_POINT('',(-31.3837139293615,-6.25,-38.));
#1056=LINE('',#1055,#1054);
#1057=CARTESIAN_POINT('',(-57.5,-6.25,-38.));
#1058=VERTEX_POINT('',#1057);
#1059=EDGE_CURVE('E860',#1058,#1015,#1056,.T.);
#1060=ORIENTED_EDGE('',*,*,#1059,.T.);
#1061=ORIENTED_EDGE('',*,*,#1032,.T.);
#1062=DIRECTION('',(1.,0.,0.));
#1063=VECTOR('',#1062,1.);
#1064=CARTESIAN_POINT('',(-31.3837139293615,-6.25,0.));
#1065=LINE('',#1064,#1063);
#1066=CARTESIAN_POINT('',(-57.5,-6.25,0.));
#1067=VERTEX_POINT('',#1066);
#1068=EDGE_CURVE('E859',#1067,#1025,#1065,.T.);
#1069=ORIENTED_EDGE('',*,*,#1068,.F.);
#1070=CARTESIAN_POINT('',(-57.5,-6.25,-19.));
#1071=DIRECTION('',(0.,-1.,0.));
#1072=DIRECTION('',(0.,0.,-1.));
#1073=AXIS2_PLACEMENT_3D('',#1070,#1071,#1072);
#1074=CIRCLE('',#1073,19.);
#1075=EDGE_CURVE('E886',#1067,#1058,#1074,.T.);
#1076=ORIENTED_EDGE('',*,*,#1075,.T.);
#1077=EDGE_LOOP('',(#1060,#1061,#1069,#1076));
#1078=FACE_BOUND('',#1077,.T.);
#1079=ADVANCED_FACE('F938',(#1052,#1078),#1041,.T.);
#1080=CARTESIAN_POINT('',(0.,0.,-38.));
#1081=DIRECTION('',(0.,0.,1.));
#1082=DIRECTION('',(1.,0.,0.));
#1083=AXIS2_PLACEMENT_3D('',#1080,#1081,#1082);
#1084=PLANE('',#1083);
#1085=DIRECTION('',(0.,1.,0.));
#1086=VECTOR('',#1085,1.);
#1087=CARTESIAN_POINT('',(-57.5,6.25,-38.));
#1088=LINE('',#1087,#1086);
#1089=CARTESIAN_POINT('',(-57.5,-1.25,-38.));
#1090=VERTEX_POINT('',#1089);
#1091=EDGE_CURVE('E828',#1058,#1090,#1088,.T.);
#1092=ORIENTED_EDGE('',*,*,#1091,.T.);
#1093=DIRECTION('',(1.,0.,0.));
#1094=VECTOR('',#1093,1.);
#1095=CARTESIAN_POINT('',(-76.5,-1.25,-38.));
#1096=LINE('',#1095,#1094);
#1097=CARTESIAN_POINT('',(-35.9713427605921,-1.25,-38.));
#1098=VERTEX_POINT('',#1097);
#1099=EDGE_CURVE('E809',#1090,#1098,#1096,.T.);
#1100=ORIENTED_EDGE('',*,*,#1099,.T.);
#1101=CARTESIAN_POINT('',(-35.9713427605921,-12.25,-38.));
#1102=DIRECTION('',(0.,0.,-1.));
#1103=DIRECTION('',(1.,0.,0.));
#1104=AXIS2_PLACEMENT_3D('',#1101,#1102,#1103);
#1105=CIRCLE('',#1104,11.);
#1106=CARTESIAN_POINT('',(-25.5585856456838,-8.70394736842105,-38.));
#1107=VERTEX_POINT('',#1106);
#1108=EDGE_CURVE('E817',#1098,#1107,#1105,.T.);
#1109=ORIENTED_EDGE('',*,*,#1108,.T.);
#1110=CARTESIAN_POINT('',(0.,0.,-38.));
#1111=DIRECTION('',(0.,0.,1.));
#1112=DIRECTION('',(1.,0.,0.));
#1113=AXIS2_PLACEMENT_3D('',#1110,#1111,#1112);
#1114=CIRCLE('',#1113,27.);
#1115=CARTESIAN_POINT('',(25.5585856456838,-8.70394736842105,-38.));
#1116=VERTEX_POINT('',#1115);
#1117=EDGE_CURVE('E822',#1107,#1116,#1114,.T.);
#1118=ORIENTED_EDGE('',*,*,#1117,.T.);
#1119=CARTESIAN_POINT('',(35.9713427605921,-12.25,-38.));
#1120=DIRECTION('',(0.,0.,-1.));
#1121=DIRECTION('',(1.,0.,0.));
#1122=AXIS2_PLACEMENT_3D('',#1119,#1120,#1121);
#1123=CIRCLE('',#1122,11.);
#1124=CARTESIAN_POINT('',(35.9713427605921,-1.25,-38.));
#1125=VERTEX_POINT('',#1124);
#1126=EDGE_CURVE('E838',#1116,#1125,#1123,.T.);
#1127=ORIENTED_EDGE('',*,*,#1126,.T.);
#1128=DIRECTION('',(1.,0.,0.));
#1129=VECTOR('',#1128,1.);
#1130=CARTESIAN_POINT('',(35.9713427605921,-1.25,-38.));
#1131=LINE('',#1130,#1129);
#1132=CARTESIAN_POINT('',(57.5,-1.25,-38.));
#1133=VERTEX_POINT('',#1132);
#1134=EDGE_CURVE('E814',#1125,#1133,#1131,.T.);
#1135=ORIENTED_EDGE('',*,*,#1134,.T.);
#1136=DIRECTION('',(0.,-1.,0.));
#1137=VECTOR('',#1136,1.);
#1138=CARTESIAN_POINT('',(57.5,-6.25,-38.));
#1139=LINE('',#1138,#1137);
#1140=EDGE_CURVE('E878',#1133,#925,#1139,.T.);
#1141=ORIENTED_EDGE('',*,*,#1140,.T.);
#1142=ORIENTED_EDGE('',*,*,#926,.F.);
#1143=ORIENTED_EDGE('',*,*,#950,.T.);
#1144=ORIENTED_EDGE('',*,*,#998,.F.);
#1145=ORIENTED_EDGE('',*,*,#1016,.T.);
#1146=ORIENTED_EDGE('',*,*,#1059,.F.);
#1147=EDGE_LOOP('',(#1092,#1100,#1109,#1118,#1127,#1135,#1141,#1142,#1143,#1144,#1145,#1146));
#1148=FACE_BOUND('',#1147,.T.);
#1149=ADVANCED_FACE('F825',(#1148),#1084,.F.);
#1150=CARTESIAN_POINT('',(0.,0.,0.));
#1151=DIRECTION('',(0.,0.,1.));
#1152=DIRECTION('',(1.,0.,0.));
#1153=AXIS2_PLACEMENT_3D('',#1150,#1151,#1152);
#1154=PLANE('',#1153);
#1155=DIRECTION('',(1.,0.,0.));
#1156=VECTOR('',#1155,1.);
#1157=CARTESIAN_POINT('',(0.,-1.25,0.));
#1158=LINE('',#1157,#1156);
#1159=CARTESIAN_POINT('',(-57.5,-1.25,0.));
#1160=VERTEX_POINT('',#1159);
#1161=CARTESIAN_POINT('',(-35.9713427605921,-1.25,0.));
#1162=VERTEX_POINT('',#1161);
#1163=EDGE_CURVE('E44',#1160,#1162,#1158,.T.);
#1164=ORIENTED_EDGE('',*,*,#1163,.F.);
#1165=DIRECTION('',(0.,-1.,0.));
#1166=VECTOR('',#1165,1.);
#1167=CARTESIAN_POINT('',(-57.5,0.,0.));
#1168=LINE('',#1167,#1166);
#1169=EDGE_CURVE('E883',#1160,#1067,#1168,.T.);
#1170=ORIENTED_EDGE('',*,*,#1169,.T.);
#1171=ORIENTED_EDGE('',*,*,#1068,.T.);
#1172=ORIENTED_EDGE('',*,*,#1026,.T.);
#1173=ORIENTED_EDGE('',*,*,#983,.T.);
#1174=ORIENTED_EDGE('',*,*,#960,.T.);
#1175=ORIENTED_EDGE('',*,*,#910,.T.);
#1176=DIRECTION('',(0.,1.,0.));
#1177=VECTOR('',#1176,1.);
#1178=CARTESIAN_POINT('',(57.5,0.,0.));
#1179=LINE('',#1178,#1177);
#1180=CARTESIAN_POINT('',(57.5,-1.25,0.));
#1181=VERTEX_POINT('',#1180);
#1182=EDGE_CURVE('E870',#909,#1181,#1179,.T.);
#1183=ORIENTED_EDGE('',*,*,#1182,.T.);
#1184=DIRECTION('',(1.,0.,0.));
#1185=VECTOR('',#1184,1.);
#1186=CARTESIAN_POINT('',(35.9713427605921,-1.25,0.));
#1187=LINE('',#1186,#1185);
#1188=CARTESIAN_POINT('',(35.9713427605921,-1.25,0.));
#1189=VERTEX_POINT('',#1188);
#1190=EDGE_CURVE('E829',#1189,#1181,#1187,.T.);
#1191=ORIENTED_EDGE('',*,*,#1190,.F.);
#1192=CARTESIAN_POINT('',(35.9713427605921,-12.25,0.));
#1193=DIRECTION('',(0.,0.,-1.));
#1194=DIRECTION('',(1.,0.,0.));
#1195=AXIS2_PLACEMENT_3D('',#1192,#1193,#1194);
#1196=CIRCLE('',#1195,11.);
#1197=CARTESIAN_POINT('',(25.5585856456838,-8.70394736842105,0.));
#1198=VERTEX_POINT('',#1197);
#1199=EDGE_CURVE('E831',#1198,#1189,#1196,.T.);
#1200=ORIENTED_EDGE('',*,*,#1199,.F.);
#1201=CARTESIAN_POINT('',(0.,0.,0.));
#1202=DIRECTION('',(0.,0.,1.));
#1203=DIRECTION('',(1.,0.,0.));
#1204=AXIS2_PLACEMENT_3D('',#1201,#1202,#1203);
#1205=CIRCLE('',#1204,27.);
#1206=CARTESIAN_POINT('',(-25.5585856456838,-8.70394736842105,0.));
#1207=VERTEX_POINT('',#1206);
#1208=EDGE_CURVE('E845',#1207,#1198,#1205,.T.);
#1209=ORIENTED_EDGE('',*,*,#1208,.F.);
#1210=CARTESIAN_POINT('',(-35.9713427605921,-12.25,0.));
#1211=DIRECTION('',(0.,0.,-1.));
#1212=DIRECTION('',(1.,0.,0.));
#1213=AXIS2_PLACEMENT_3D('',#1210,#1211,#1212);
#1214=CIRCLE('',#1213,11.);
#1215=EDGE_CURVE('E843',#1162,#1207,#1214,.T.);
#1216=ORIENTED_EDGE('',*,*,#1215,.F.);
#1217=EDGE_LOOP('',(#1164,#1170,#1171,#1172,#1173,#1174,#1175,#1183,#1191,#1200,#1209,#1216));
#1218=FACE_BOUND('',#1217,.T.);
#1219=ADVANCED_FACE('F944',(#1218),#1154,.T.);
#1220=CARTESIAN_POINT('',(57.5,-6.25,-19.));
#1221=DIRECTION('',(0.,1.,0.));
#1222=DIRECTION('',(-1.,0.,0.));
#1223=AXIS2_PLACEMENT_3D('',#1220,#1221,#1222);
#1224=CYLINDRICAL_SURFACE('',#1223,19.);
#1225=CARTESIAN_POINT('',(57.5,-1.25,-19.));
#1226=DIRECTION('',(0.,-1.,0.));
#1227=DIRECTION('',(0.,0.,-1.));
#1228=AXIS2_PLACEMENT_3D('',#1225,#1226,#1227);
#1229=CIRCLE('',#1228,19.);
#1230=EDGE_CURVE('E852',#1181,#1133,#1229,.F.);
#1231=ORIENTED_EDGE('',*,*,#1230,.F.);
#1232=ORIENTED_EDGE('',*,*,#1182,.F.);
#1233=ORIENTED_EDGE('',*,*,#933,.F.);
#1234=ORIENTED_EDGE('',*,*,#1140,.F.);
#1235=EDGE_LOOP('',(#1231,#1232,#1233,#1234));
#1236=FACE_BOUND('',#1235,.T.);
#1237=ADVANCED_FACE('F959',(#1236),#1224,.T.);
#1238=CARTESIAN_POINT('',(-57.5,6.25,-19.));
#1239=DIRECTION('',(0.,-1.,0.));
#1240=DIRECTION('',(1.,0.,0.));
#1241=AXIS2_PLACEMENT_3D('',#1238,#1239,#1240);
#1242=CYLINDRICAL_SURFACE('',#1241,19.);
#1243=CARTESIAN_POINT('',(-57.5,-1.25,-19.));
#1244=DIRECTION('',(0.,-1.,0.));
#1245=DIRECTION('',(0.,0.,-1.));
#1246=AXIS2_PLACEMENT_3D('',#1243,#1244,#1245);
#1247=CIRCLE('',#1246,19.);
#1248=EDGE_CURVE('E857',#1090,#1160,#1247,.F.);
#1249=ORIENTED_EDGE('',*,*,#1248,.F.);
#1250=ORIENTED_EDGE('',*,*,#1091,.F.);
#1251=ORIENTED_EDGE('',*,*,#1075,.F.);
#1252=ORIENTED_EDGE('',*,*,#1169,.F.);
#1253=EDGE_LOOP('',(#1249,#1250,#1251,#1252));
#1254=FACE_BOUND('',#1253,.T.);
#1255=ADVANCED_FACE('F943',(#1254),#1242,.T.);
#1256=CARTESIAN_POINT('',(-35.9713427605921,-12.25,-38.));
#1257=DIRECTION('',(0.,0.,1.));
#1258=DIRECTION('',(1.,0.,0.));
#1259=AXIS2_PLACEMENT_3D('',#1256,#1257,#1258);
#1260=CYLINDRICAL_SURFACE('',#1259,11.);
#1261=ORIENTED_EDGE('',*,*,#1215,.T.);
#1262=DIRECTION('',(0.,0.,1.));
#1263=VECTOR('',#1262,1.);
#1264=CARTESIAN_POINT('',(-25.5585856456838,-8.70394736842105,-38.));
#1265=LINE('',#1264,#1263);
#1266=EDGE_CURVE('E813',#1107,#1207,#1265,.T.);
#1267=ORIENTED_EDGE('',*,*,#1266,.F.);
#1268=ORIENTED_EDGE('',*,*,#1108,.F.);
#1269=DIRECTION('',(0.,0.,1.));
#1270=VECTOR('',#1269,1.);
#1271=CARTESIAN_POINT('',(-35.9713427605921,-1.25,-38.));
#1272=LINE('',#1271,#1270);
#1273=EDGE_CURVE('E735',#1098,#1162,#1272,.T.);
#1274=ORIENTED_EDGE('',*,*,#1273,.T.);
#1275=EDGE_LOOP('',(#1261,#1267,#1268,#1274));
#1276=FACE_BOUND('',#1275,.T.);
#1277=ADVANCED_FACE('F818',(#1276),#1260,.T.);
#1278=CARTESIAN_POINT('',(0.,0.,-38.));
#1279=DIRECTION('',(0.,0.,1.));
#1280=DIRECTION('',(1.,0.,0.));
#1281=AXIS2_PLACEMENT_3D('',#1278,#1279,#1280);
#1282=CYLINDRICAL_SURFACE('',#1281,27.);
#1283=ORIENTED_EDGE('',*,*,#1208,.T.);
#1284=DIRECTION('',(0.,0.,1.));
#1285=VECTOR('',#1284,1.);
#1286=CARTESIAN_POINT('',(25.5585856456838,-8.70394736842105,-38.));
#1287=LINE('',#1286,#1285);
#1288=EDGE_CURVE('E853',#1116,#1198,#1287,.T.);
#1289=ORIENTED_EDGE('',*,*,#1288,.F.);
#1290=ORIENTED_EDGE('',*,*,#1117,.F.);
#1291=ORIENTED_EDGE('',*,*,#1266,.T.);
#1292=EDGE_LOOP('',(#1283,#1289,#1290,#1291));
#1293=FACE_BOUND('',#1292,.T.);
#1294=ADVANCED_FACE('F949',(#1293),#1282,.F.);
#1295=CARTESIAN_POINT('',(35.9713427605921,-12.25,-38.));
#1296=DIRECTION('',(0.,0.,1.));
#1297=DIRECTION('',(1.,0.,0.));
#1298=AXIS2_PLACEMENT_3D('',#1295,#1296,#1297);
#1299=CYLINDRICAL_SURFACE('',#1298,11.);
#1300=ORIENTED_EDGE('',*,*,#1199,.T.);
#1301=DIRECTION('',(0.,0.,1.));
#1302=VECTOR('',#1301,1.);
#1303=CARTESIAN_POINT('',(35.9713427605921,-1.25,-38.));
#1304=LINE('',#1303,#1302);
#1305=EDGE_CURVE('E850',#1125,#1189,#1304,.T.);
#1306=ORIENTED_EDGE('',*,*,#1305,.F.);
#1307=ORIENTED_EDGE('',*,*,#1126,.F.);
#1308=ORIENTED_EDGE('',*,*,#1288,.T.);
#1309=EDGE_LOOP('',(#1300,#1306,#1307,#1308));
#1310=FACE_BOUND('',#1309,.T.);
#1311=ADVANCED_FACE('F954',(#1310),#1299,.T.);
#1312=CARTESIAN_POINT('',(35.9713427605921,-1.25,-38.));
#1313=DIRECTION('',(0.,-1.,0.));
#1314=DIRECTION('',(0.,0.,-1.));
#1315=AXIS2_PLACEMENT_3D('',#1312,#1313,#1314);
#1316=PLANE('',#1315);
#1317=CARTESIAN_POINT('',(57.5,-1.24999999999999,-19.));
#1318=DIRECTION('',(0.,-1.,0.));
#1319=DIRECTION('',(0.,0.,-1.));
#1320=AXIS2_PLACEMENT_3D('',#1317,#1318,#1319);
#1321=CIRCLE('',#1320,6.5);
#1322=CARTESIAN_POINT('',(57.5,-1.24999999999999,-25.5));
#1323=VERTEX_POINT('',#1322);
#1324=EDGE_CURVE('E722',#1323,#1323,#1321,.T.);
#1325=ORIENTED_EDGE('',*,*,#1324,.T.);
#1326=EDGE_LOOP('',(#1325));
#1327=FACE_BOUND('',#1326,.T.);
#1328=ORIENTED_EDGE('',*,*,#1230,.T.);
#1329=ORIENTED_EDGE('',*,*,#1134,.F.);
#1330=ORIENTED_EDGE('',*,*,#1305,.T.);
#1331=ORIENTED_EDGE('',*,*,#1190,.T.);
#1332=EDGE_LOOP('',(#1328,#1329,#1330,#1331));
#1333=FACE_BOUND('',#1332,.T.);
#1334=ADVANCED_FACE('F956',(#1327,#1333),#1316,.F.);
#1335=CARTESIAN_POINT('',(-76.5,-1.25,-38.));
#1336=DIRECTION('',(0.,-1.,0.));
#1337=DIRECTION('',(0.,0.,-1.));
#1338=AXIS2_PLACEMENT_3D('',#1335,#1336,#1337);
#1339=PLANE('',#1338);
#1340=CARTESIAN_POINT('',(-57.5,-1.25,-19.));
#1341=DIRECTION('',(0.,-1.,0.));
#1342=DIRECTION('',(0.,0.,-1.));
#1343=AXIS2_PLACEMENT_3D('',#1340,#1341,#1342);
#1344=CIRCLE('',#1343,6.5);
#1345=CARTESIAN_POINT('',(-57.5,-1.25,-25.5));
#1346=VERTEX_POINT('',#1345);
#1347=EDGE_CURVE('E903',#1346,#1346,#1344,.T.);
#1348=ORIENTED_EDGE('',*,*,#1347,.T.);
#1349=EDGE_LOOP('',(#1348));
#1350=FACE_BOUND('',#1349,.T.);
#1351=ORIENTED_EDGE('',*,*,#1248,.T.);
#1352=ORIENTED_EDGE('',*,*,#1163,.T.);
#1353=ORIENTED_EDGE('',*,*,#1273,.F.);
#1354=ORIENTED_EDGE('',*,*,#1099,.F.);
#1355=EDGE_LOOP('',(#1351,#1352,#1353,#1354));
#1356=FACE_BOUND('',#1355,.T.);
#1357=ADVANCED_FACE('F807',(#1350,#1356),#1339,.F.);
#1358=CARTESIAN_POINT('',(-57.5,57.5,-19.));
#1359=DIRECTION('',(0.,-1.,0.));
#1360=DIRECTION('',(0.,0.,-1.));
#1361=AXIS2_PLACEMENT_3D('',#1358,#1359,#1360);
#1362=CYLINDRICAL_SURFACE('',#1361,6.5);
#1363=ORIENTED_EDGE('',*,*,#1049,.T.);
#1364=EDGE_LOOP('',(#1363));
#1365=FACE_BOUND('',#1364,.T.);
#1366=ORIENTED_EDGE('',*,*,#1347,.F.);
#1367=EDGE_LOOP('',(#1366));
#1368=FACE_BOUND('',#1367,.T.);
#1369=ADVANCED_FACE('F990',(#1365,#1368),#1362,.F.);
#1370=CARTESIAN_POINT('',(57.5,57.5,-19.));
#1371=DIRECTION('',(0.,-1.,0.));
#1372=DIRECTION('',(0.,0.,-1.));
#1373=AXIS2_PLACEMENT_3D('',#1370,#1371,#1372);
#1374=CYLINDRICAL_SURFACE('',#1373,6.5);
#1375=ORIENTED_EDGE('',*,*,#898,.T.);
#1376=EDGE_LOOP('',(#1375));
#1377=FACE_BOUND('',#1376,.T.);
#1378=ORIENTED_EDGE('',*,*,#1324,.F.);
#1379=EDGE_LOOP('',(#1378));
#1380=FACE_BOUND('',#1379,.T.);
#1381=ADVANCED_FACE('F915',(#1377,#1380),#1374,.F.);
#1382=CLOSED_SHELL('',(#937,#970,#1003,#1036,#1079,#1149,#1219,#1237,#1255,#1277,#1294,#1311,
#1334,#1357,#1369,#1381));
#1383=MANIFOLD_SOLID_BREP('B6',#1382);
#1384=ADVANCED_BREP_SHAPE_REPRESENTATION('',(#18,#885,#1383),#14);
#1385=SHAPE_DEFINITION_REPRESENTATION(#9,#1384);
ENDSEC;
END-ISO-10303-21;
